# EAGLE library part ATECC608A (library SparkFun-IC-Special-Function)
ATECC608A CryptoAuthentication Device Cryptographic Co-processor with Secure Hardware-Based Key Storage ECDSA: FIPS186-3 Elliptic Curve Digital Signature Algorithm ECDH: FIPS SP800-56A Elliptic Curve Diffie-Hellman Algorithm AES Algorithm for encryption and decryption NIST Standard P256 Elliptic Curve Support SHA-256 Hash Algorithm with HMAC Option 1 MHz Standard I2C Interface 2.0V to 5.5V Supply Voltage Range 1.8V to 5.5V IO levels Datasheet (summary) SparkFun Products SparkFun Cryptographic Co-Processor Breakout - ATECC608A (Qwiic) (DEV-18077)

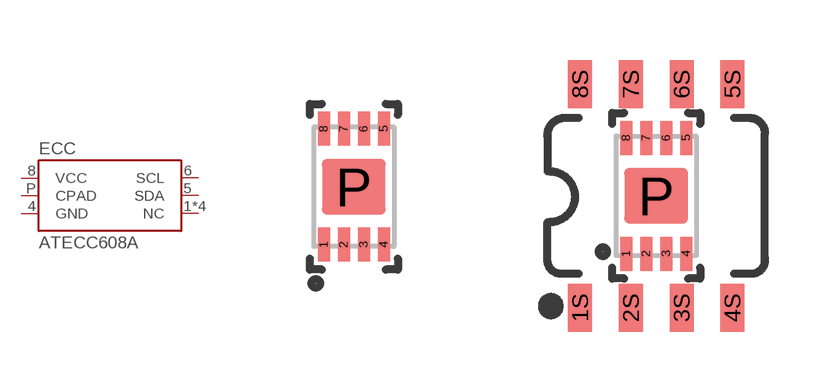
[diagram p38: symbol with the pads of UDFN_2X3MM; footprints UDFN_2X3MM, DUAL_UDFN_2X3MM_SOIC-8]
Designator prefix ECC

## ATECC608AUDFN_2X3MM (PROD_ID: IC-15933)  [UDFN_2X3MM]
1  NC  nc
2  NC  nc
3  NC  nc
4  GND  pwr
5  SDA
6  SCL
7  NC  nc
8  VCC  pwr
P  CPAD  pwr

## ATECC608ADUAL_PACKAGE_UDFN_SOIC-8 (PROD_ID: IC-15951)  [DUAL_UDFN_2X3MM_SOIC-8]
1  NC  nc
1S  NC  nc
2  NC  nc
2S  NC  nc
3  NC  nc
3S  NC  nc
4  GND  pwr
4S  GND  pwr
5  SDA
5S  SDA
6  SCL
6S  SCL
7  NC  nc
7S  NC  nc
8  VCC  pwr
8S  VCC  pwr
P  CPAD  pwr

## Footprint UDFN_2X3MM (pad centres in mm)
smd 0.3 x 0.85: 1 -0.75,-1.45; 2 -0.25,-1.45; 3 0.25,-1.45; 4 0.75,-1.45; 5 0.75,1.45; 6 0.25,1.45; 7 -0.25,1.45; 8 -0.75,1.45
smd 1.6 x 1.4: P 0,0

## Footprint DUAL_UDFN_2X3MM_SOIC-8 (pad centres in mm)
smd 0.3 x 0.85: 1 -0.75,-1.45; 2 -0.25,-1.45; 3 0.25,-1.45; 4 0.75,-1.45; 5 0.75,1.45; 6 0.25,1.45; 7 -0.25,1.45; 8 -0.75,1.45
smd 0.6 x 1.2: 1S -1.905,-2.8; 2S -0.635,-2.8; 3S 0.635,-2.8; 4S 1.905,-2.8; 5S 1.905,2.8; 6S 0.635,2.8; 7S -0.635,2.8; 8S -1.905,2.8
smd 1.6 x 1.4: P 0,0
